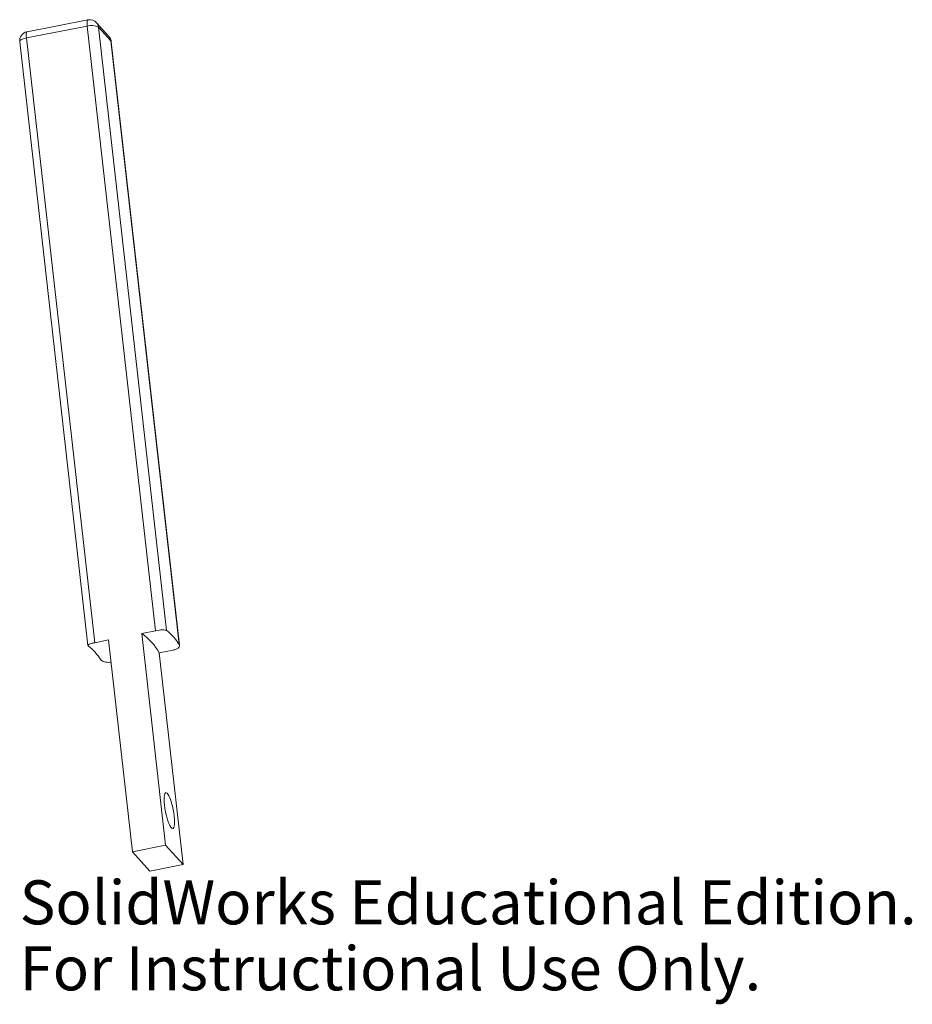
# Model space of a CAD drawing. Units: millimetres. Extents: x -27 to 71, y -6 to 102.
import ezdxf

# ---------------------------------------------------------------- set-up
doc = ezdxf.new("R2010")
doc.units = ezdxf.units.MM
doc.styles.add('SLDTEXTSTYLE0', font='TXT', dxfattribs={"width": 0.7})

msp = doc.modelspace()

# ---------------------------------------------------------------- linework, layer by layer
at = {"color": 7, "linetype": 'Continuous', "lineweight": 15}
for p, q in [((-19.67, 102.1), (-26.37, 100.79)), ((-17.36, 100.26), (-18.73, 101.79)), ((-19.74, 101.42), (-26.44, 100.11)), ((-12.23, 34.95), (-19.74, 101.42)), ((-18.52, 101.31), (-11.02, 34.98)), ((-17.14, 99.78), (-18.52, 101.31)), ((-27.17, 99.7), (-19.67, 33.34)), ((-26.44, 100.11), (-18.93, 33.64)), ((-9.64, 33.45), (-17.14, 99.78)), ((-9.6, 33.35), (-17.11, 99.7)), ((-13.76, 34.65), (-12.23, 34.95)), ((-13.76, 34.65), (-11.13, 11.38)), ((-18.93, 33.64), (-17.4, 33.94)), ((-14.76, 10.66), (-17.4, 33.94)), ((-10.32, 32.82), (-11.85, 32.52)), ((-9.22, 9.25), (-11.85, 32.52)), ((-14.76, 10.66), (-11.13, 11.38)), ((-11.13, 11.38), (-9.22, 9.25)), ((-12.85, 8.53), (-14.76, 10.66)), ((-12.85, 8.53), (-9.22, 9.25))]:
    msp.add_line(p, q, dxfattribs=at)
at = {"color": 7, "linetype": 'Continuous', "lineweight": 15, "flags": 128}
for points in [[(-19.74, 101.42), (-19.76, 101.6), (-19.76, 101.76), (-19.76, 101.89), (-19.74, 102), (-19.71, 102.07), (-19.68, 102.1), (-19.67, 102.1)], [(-26.44, 100.11), (-26.46, 100.29), (-26.46, 100.44), (-26.46, 100.58), (-26.44, 100.68), (-26.41, 100.75), (-26.38, 100.79), (-26.37, 100.79)], [(-26.44, 100.11), (-26.63, 100.07), (-26.79, 100.01), (-26.93, 99.95), (-27.04, 99.89), (-27.12, 99.82), (-27.16, 99.75), (-27.17, 99.7)], [(-17.11, 99.7), (-17.11, 99.72), (-17.14, 99.78)], [(-10.18, 14.58), (-10.15, 14.24), (-10.14, 13.94), (-10.15, 13.68), (-10.18, 13.47), (-10.23, 13.32), (-10.29, 13.23), (-10.37, 13.21), (-10.46, 13.26), (-10.56, 13.37), (-10.67, 13.54), (-10.77, 13.77), (-10.88, 14.04), (-10.98, 14.36), (-11.07, 14.7), (-11.15, 15.06), (-11.21, 15.42), (-11.26, 15.78), (-11.29, 16.11), (-11.3, 16.41), (-11.29, 16.67), (-11.26, 16.88), (-11.21, 17.03), (-11.15, 17.12), (-11.07, 17.14), (-10.98, 17.09), (-10.88, 16.98), (-10.78, 16.81), (-10.67, 16.58), (-10.57, 16.31), (-10.47, 15.99), (-10.38, 15.65), (-10.3, 15.29), (-10.23, 14.93), (-10.18, 14.58)]]:
    msp.add_lwpolyline(points, dxfattribs=at)
at = {"color": 7, "linetype": 'Continuous', "lineweight": 15}
for centre, radius, start, end in [((-19.47, 101.12), 1, 41.8966, 101.0859), ((-19.37, 101.22), 0.86, 6.1428, 41.6922), ((-26.18, 99.81), 1, 101.0859, 186.4519), ((-19.27, 99.86), 1.63, 62.5768, 106.9665), ((-18.1, 99.59), 1, 6.4519, 41.8966), ((-18, 99.69), 0.86, 6.1428, 41.6922), ((-17.03, 29.8), 5.85, 27.7448, 56.0485), ((-14.65, 30.34), 5.89, 31.8563, 51.937), ((-23.27, 28.65), 5.89, 31.8563, 51.937)]:
    msp.add_arc(centre, radius, start, end, dxfattribs=at)
for points, knots in [([(-11.02, 34.98), (-11.05, 35.01), (-11.11, 35.02), (-11.26, 35.04), (-11.36, 35.05), (-11.7, 35.04), (-11.97, 35), (-12.23, 34.95)], [0, 0, 0, 0, 0.25, 0.25, 0.5, 0.5, 1, 1, 1, 1]), ([(-18.93, 33.64), (-19.06, 33.61), (-19.17, 33.59), (-19.38, 33.53), (-19.47, 33.5), (-19.6, 33.43), (-19.64, 33.4), (-19.67, 33.35), (-19.67, 33.32), (-19.63, 33.3)], [0, 0, 0, 0, 0.25, 0.25, 0.5, 0.5, 0.75, 0.75, 1, 1, 1, 1]), ([(-10.32, 32.82), (-10.19, 32.85), (-10.07, 32.88), (-9.87, 32.98), (-9.78, 33.03), (-9.66, 33.15), (-9.62, 33.21), (-9.6, 33.34), (-9.61, 33.4), (-9.64, 33.45)], [0, 0, 0, 0, 0.25, 0.25, 0.5, 0.5, 0.75, 0.75, 1, 1, 1, 1]), ([(-18.26, 31.77), (-18.22, 31.72), (-18.13, 31.63), (-17.88, 31.53), (-17.57, 31.47), (-17.3, 31.47), (-17.15, 31.49), (-17.12, 31.49)], [0, 0, 0, 0, 0.2327198, 0.4654338, 0.6979965, 0.9282563, 1, 1, 1, 1])]:
    msp.add_open_spline(points, degree=3, knots=knots, dxfattribs=at)

# ---------------------------------------------------------------- texts
at = {"color": 7, "linetype": 'Continuous', "char_height": 4.8336, "attachment_point": 1, "style": 'SLDTEXTSTYLE0'}
for s, insert in [('SolidWorks Educational Edition.', (-27.18, 7.51)), ('For Instructional Use Only.', (-27.18, 0.26))]:
    msp.add_mtext(s, dxfattribs=dict(at, insert=insert))

doc.saveas('drawing.dxf')
